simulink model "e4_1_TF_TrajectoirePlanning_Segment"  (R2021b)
settings: Solver=FixedStepAuto  StartTime=0.0  StopTime=50  FixedStep=sampleTime  RelTol=1e-3  EnableMultiTasking=on
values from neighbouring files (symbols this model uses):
  k2_d_x = 1/1    (= 1)    [e4_1_TF_TrajectoirePlanning_code.m]    (also in e4_1_Model_TrajectoirePlanning_HITL_code.m = 0.5; e4_3_Model_TrajectoirePlanning_code.m = 0.5; e4_1_Model_TrajectoirePlanning_code.m = 0.5; e4_2_TF_TrajectoirePlanning_code.m)
  k2_d_y = 1/1    (= 1)    [e4_1_TF_TrajectoirePlanning_code.m]    (also in e4_1_Model_TrajectoirePlanning_HITL_code.m = 0.377358490566; e4_3_Model_TrajectoirePlanning_code.m = 0.377358490566; e4_1_Model_TrajectoirePlanning_code.m = 0.377358490566; e4_2_TF_TrajectoirePlanning_code.m)
  k2_d_z = 10    [e4_1_TF_TrajectoirePlanning_code.m]    (also in e4_1_Model_TrajectoirePlanning_HITL_code.m; e4_3_Model_TrajectoirePlanning_code.m; e4_1_Model_TrajectoirePlanning_code.m; e4_2_TF_TrajectoirePlanning_code.m)
  k2_p_x = 1/0.8    (= 1.25)    [e4_1_TF_TrajectoirePlanning_code.m]    (also in e4_1_Model_TrajectoirePlanning_HITL_code.m = 0.645161290323; e4_3_Model_TrajectoirePlanning_code.m = 0.645161290323; e4_1_Model_TrajectoirePlanning_code.m = 0.645161290323; e4_2_TF_TrajectoirePlanning_code.m)
  k2_p_y = 1/0.8    (= 1.25)    [e4_1_TF_TrajectoirePlanning_code.m]    (also in e4_1_Model_TrajectoirePlanning_HITL_code.m = 0.4; e4_3_Model_TrajectoirePlanning_code.m = 0.4; e4_1_Model_TrajectoirePlanning_code.m = 0.4; e4_2_TF_TrajectoirePlanning_code.m)
  k2_p_yaw = 1.6    [e4_1_TF_TrajectoirePlanning_code.m]    (also in e4_1_Model_TrajectoirePlanning_HITL_code.m; e4_3_Model_TrajectoirePlanning_code.m; e4_1_Model_TrajectoirePlanning_code.m; e4_2_TF_TrajectoirePlanning_code.m)
  k2_p_z = 1    [e4_1_TF_TrajectoirePlanning_code.m]    (also in e4_1_Model_TrajectoirePlanning_HITL_code.m; e4_3_Model_TrajectoirePlanning_code.m; e4_1_Model_TrajectoirePlanning_code.m; e4_2_TF_TrajectoirePlanning_code.m)
  sampleTime = 0.01    [startSimulation.m]    (also in start.m)
  saturation_psi = 2    [startSimulation.m]    (also in start.m)
  saturation_x = 2    [startSimulation.m]    (also in start.m)
  saturation_y = 2    [startSimulation.m]    (also in start.m)
  saturation_z = 2    [startSimulation.m]    (also in start.m)
libraries: aerolibanimutils x1

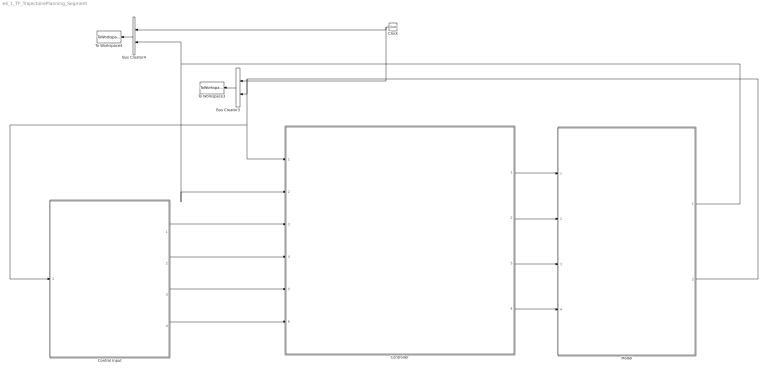
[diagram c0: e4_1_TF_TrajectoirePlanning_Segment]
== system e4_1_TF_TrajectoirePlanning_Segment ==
  Bus Creator3 : BusCreator  Inputs=2
  Bus Creator4 : BusCreator  Inputs=2
  Clock : Clock
  Control Input : Subsystem
  "Controller " : Subsystem
  Model : Subsystem
  To Workspace3 : ToWorkspace  VariableName=r1_pos_array  SampleTime=-1
  To Workspace4 : ToWorkspace  VariableName=r1_vel_array  SampleTime=-1
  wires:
  Clock/1 -> Bus Creator4/1, Bus Creator3/1
  Bus Creator3/1 -> To Workspace3/1
  Bus Creator4/1 -> To Workspace4/1
  "Controller "/1(Controller Output X) -> Model/1(Commande Input X)
  "Controller "/2(Controller Output Y) -> Model/2(Commande Input Y)
  "Controller "/3(Controller Output H) -> Model/3(Commande Input H)
  "Controller "/4(Controller Output Psi) -> Model/4(Commande Input Psi)
  Control Input/1(ux) -> "Controller "/3(Control input X)
  Control Input/2(uy) -> "Controller "/4(Control input Y)
  Control Input/3(uz) -> "Controller "/5(Control input H)
  Control Input/4(upsi) -> "Controller "/6(Control input Psi)
  Model/2(Output Position) -> "Controller "/1(Feedback Position), Control Input/1(Position Feedback), Bus Creator3/2
  Model/1(Output Velocity) -> "Controller "/2(Feedback Velocity), Bus Creator4/2

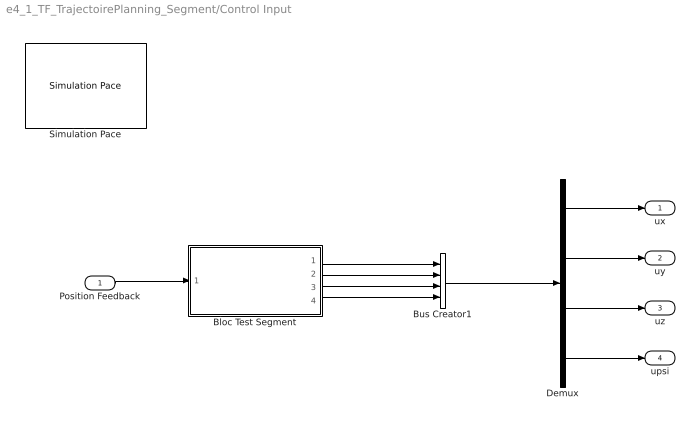
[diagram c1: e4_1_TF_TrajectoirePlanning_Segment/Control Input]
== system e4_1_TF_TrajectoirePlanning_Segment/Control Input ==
  Position Feedback : Inport
  Bloc Test Segment : Subsystem
  Bus Creator1 : BusCreator  Inputs=4
  Demux : Demux
  Simulation Pace : aerolibanimutils/Simulation Pace  SimulationPace=100  SleepMode=MATLAB Thread  OutputPaceError=off  SampleTime=-1
  ux : Outport  VectorParamsAs1DForOutWhenUnconnected=off
  uy : Outport  Port=2  VectorParamsAs1DForOutWhenUnconnected=off
  uz : Outport  Port=3  VectorParamsAs1DForOutWhenUnconnected=off
  upsi : Outport  Port=4  VectorParamsAs1DForOutWhenUnconnected=off
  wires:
  Demux/2 -> uy/1
  Demux/1 -> ux/1
  Demux/3 -> uz/1
  Demux/4 -> upsi/1
  Bloc Test Segment/4(upsi) -> Bus Creator1/4
  Bloc Test Segment/3(uz) -> Bus Creator1/3
  Bloc Test Segment/1(ux) -> Bus Creator1/1
  Bloc Test Segment/2(uy) -> Bus Creator1/2
  Bus Creator1/1 -> Demux/1
  Position Feedback/1 -> Bloc Test Segment/1(Position Feedback)

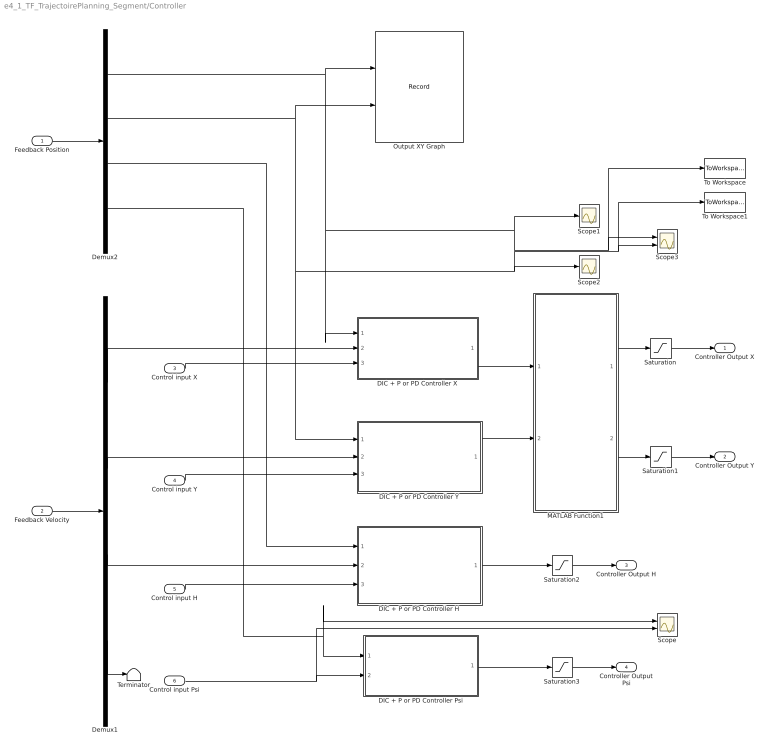
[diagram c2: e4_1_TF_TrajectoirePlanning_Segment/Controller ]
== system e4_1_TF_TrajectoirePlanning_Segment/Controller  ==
  Feedback Position : Inport
  Feedback Velocity : Inport  Port=2
  Control input X : Inport  Port=3
  Control input Y : Inport  Port=4
  Control input H : Inport  Port=5
  Control input Psi : Inport  Port=6
  DIC + P or PD Controller H : Subsystem
  DIC + P or PD Controller Psi : Subsystem
  DIC + P or PD Controller X : Subsystem
  DIC + P or PD Controller Y : Subsystem
  Demux1 : Demux
  Demux2 : Demux
  MATLAB Function1 : MATLAB Function  TreatAsAtomicUnit=on
  Output XY Graph : Record  FileSettingsInternal="{\"entries\":[{\"content\":{\"excelSettings\":{\"content\":{},\"type\":\"Streamout.ExcelSettings\"}},\"type\":\"Streamout.FileSettingStorage\",\"uuid\":\"9feb89c2-4773-4780-905a-99dce9075acd\"}],\"packageUris\":[\"http://schema.mathworks.com/mf0/streamout_blocks/R2020a\"],\"version\":\"1.0\"}"  Layout=[1 1]  SignalsInternal="{\"entries\":[{\"content\":{\"signals\":[{\"content\":{\"blockPath\":[\"e4_1_TF_TrajectoirePlanning_Segment/Controller /Output XY Graph\"],\"channel\":[],\"dimensions\":[1],\"domain\":\"e4_1_TF_TrajectoirePlanning_Segment/Controller /Output XY Graph\",\"lineColor\":\"#a2142f\",\"plots\":[1],\"port\":1,\"sid\":[\"\"],\"signalID\":2135,\"signalName\":\"Demux2:1\"},\"type\":\"RecordBlkView.Signal\",\"uuid\":\"850235fc-df35-4988-83aa-f6efe43694d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"  VisualizationBindings="{\"xyplotplugin\":{\"info\":[{\"series\":[{\"bindingParametersList\":[{\"parameter\":\"X-Axis\",\"signalID\":2135,\"signalName\":\"Demux2:1\"},{\"parameter\":\"Y-Axis\",\"signalID\":2139,\"signalName\":\"Demux2:2\"}],\"seriesID\":35699}],\"subplotID\":1}]}}"  CompatibilityTag=XY  st=-1
  Saturation : Saturate  UpperLimit=saturation_x  LowerLimit=-saturation_x
  Saturation1 : Saturate  UpperLimit=saturation_y  LowerLimit=-saturation_y
  Saturation2 : Saturate  UpperLimit=saturation_z  LowerLimit=-saturation_z
  Saturation3 : Saturate  UpperLimit=saturation_psi  LowerLimit=-saturation_psi
  Scope : Scope  NumInputPorts=2
  Scope1 : Scope
  Scope2 : Scope
  Scope3 : Scope  NumInputPorts=2
  Terminator : Terminator
  To Workspace : ToWorkspace  VariableName=x_desire  SampleTime=-1
  To Workspace1 : ToWorkspace  VariableName=y_desire  SampleTime=-1
  Controller Output X : Outport  VectorParamsAs1DForOutWhenUnconnected=off
  Controller Output Y : Outport  Port=2  VectorParamsAs1DForOutWhenUnconnected=off
  Controller Output H : Outport  Port=3  VectorParamsAs1DForOutWhenUnconnected=off
  Controller Output Psi : Outport  Port=4  VectorParamsAs1DForOutWhenUnconnected=off
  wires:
  Feedback Position/1 -> Demux2/1
  Feedback Velocity/1 -> Demux1/1
  Demux1/2 -> DIC + P or PD Controller Y/2(Feedback Velocity Y)
  Demux2/3 -> DIC + P or PD Controller H/1(Feedback Position H)
  Demux1/1 -> DIC + P or PD Controller X/2(Feedback Velocity X)
  Demux1/3 -> DIC + P or PD Controller H/2(Feedback Velocity H)
  Control input X/1 -> DIC + P or PD Controller X/3(Control Input X)
  Control input Psi/1 -> Scope/2, DIC + P or PD Controller Psi/2(Control input Psi)
  Control input H/1 -> DIC + P or PD Controller H/3(Control Input H)
  Saturation/1 -> Controller Output X/1
  Saturation1/1 -> Controller Output Y/1
  Saturation2/1 -> Controller Output H/1
  Saturation3/1 -> Controller Output Psi/1
  Control input Y/1 -> DIC + P or PD Controller Y/3(Control Input Y)
  DIC + P or PD Controller H/1(Controller Output H) -> Saturation2/1
  DIC + P or PD Controller Psi/1(Controller Output Psi) -> Saturation3/1
  Demux2/4 -> Scope/1, DIC + P or PD Controller Psi/1(Feedback Position Psi)
  Demux1/4 -> Terminator/1
  DIC + P or PD Controller X/1(Controller Output X) -> MATLAB Function1/1(eax)
  DIC + P or PD Controller Y/1(Controller Output Y) -> MATLAB Function1/2(eay)
  MATLAB Function1/2(phi) -> Saturation1/1
  MATLAB Function1/1(theta) -> Saturation/1
  Demux2/2 -> DIC + P or PD Controller Y/1(Feedback Position Y), To Workspace1/1, Scope3/2, Scope2/1, Output XY Graph/2
  Demux2/1 -> DIC + P or PD Controller X/1(Feedback Position X), To Workspace/1, Scope3/1, Scope1/1, Output XY Graph/1

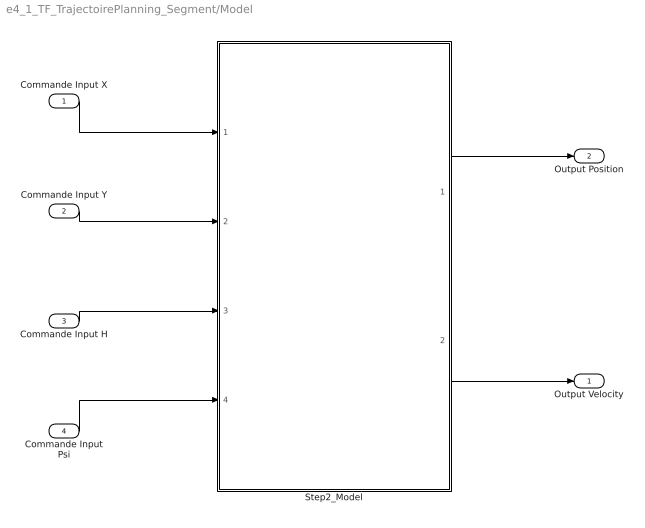
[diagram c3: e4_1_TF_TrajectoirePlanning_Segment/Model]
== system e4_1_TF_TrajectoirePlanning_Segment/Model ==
  Commande Input X : Inport
  Commande Input Y : Inport  Port=2
  Commande Input H : Inport  Port=3
  Commande Input Psi : Inport  Port=4
  Step2_Model : Subsystem
  Output Velocity : Outport  VectorParamsAs1DForOutWhenUnconnected=off
  Output Position : Outport  Port=2  VectorParamsAs1DForOutWhenUnconnected=off
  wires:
  Commande Input Y/1 -> Step2_Model/2(In2)
  Commande Input Psi/1 -> Step2_Model/4(In4)
  Commande Input H/1 -> Step2_Model/3(In3)
  Step2_Model/1(Position) -> Output Position/1
  Commande Input X/1 -> Step2_Model/1(In1)
  Step2_Model/2(Velocity) -> Output Velocity/1

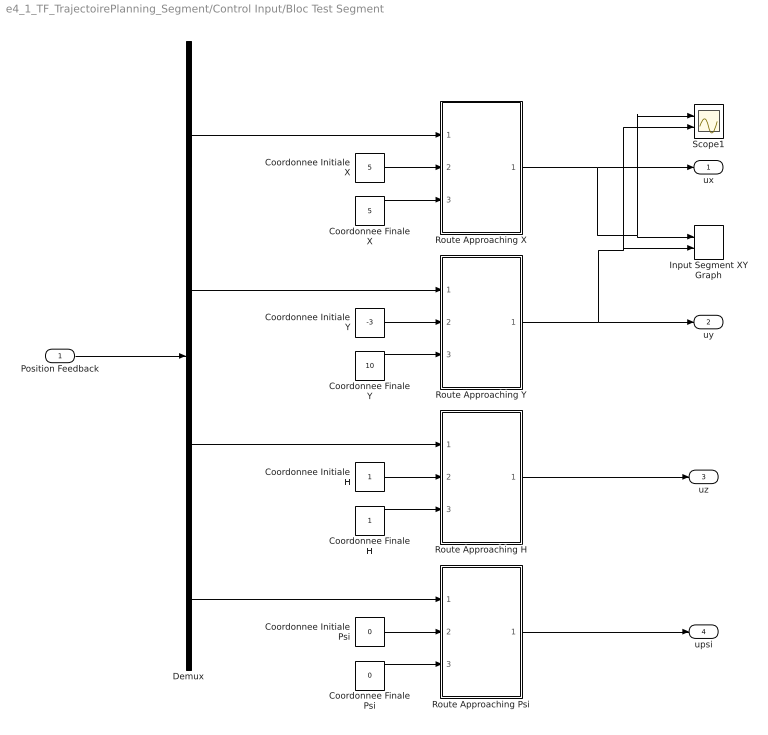
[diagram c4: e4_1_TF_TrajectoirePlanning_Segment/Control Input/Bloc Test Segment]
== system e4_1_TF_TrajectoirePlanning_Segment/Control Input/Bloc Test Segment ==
  Position Feedback : Inport
  Coordonnee Finale H : Constant
  Coordonnee Finale Psi : Constant  Value=0
  Coordonnee Finale X : Constant  Value=5
  Coordonnee Finale Y : Constant  Value=10
  Coordonnee Initiale H : Constant
  Coordonnee Initiale Psi : Constant  Value=0
  Coordonnee Initiale X : Constant  Value=5
  Coordonnee Initiale Y : Constant  Value=-3
  Demux : Demux
  Input Segment XY Graph : Record  FileSettingsInternal="{\"entries\":[{\"content\":{\"excelSettings\":{\"content\":{},\"type\":\"Streamout.ExcelSettings\"}},\"type\":\"Streamout.FileSettingStorage\",\"uuid\":\"c52b156f-2882-4037-81dc-cd67c67cff84\"}],\"packageUris\":[\"http://schema.mathworks.com/mf0/streamout_blocks/R2020a\"],\"version\":\"1.0\"}"  Layout=[1 1]  SignalsInternal="{\"entries\":[{\"content\":{\"signals\":[{\"content\":{\"blockPath\":[\"e4_1_TF_TrajectoirePlanning_Segment/Control Input/Bloc Test  Segment/Input Segment XY Graph\"],\"channel\":[],\"dimensions\":[1],\"domain\":\"e4_1_TF_TrajectoirePlanning_Segment/Control Input/Bloc Test  Segment/Input Segment XY Graph\",\"lineColor\":\"#a2142f\",\"plots\":[1],\"port\":1,\"sid\":[\"\"],\"signalID\":2127,\"signalName\":\"Route Approaching X\"},\"type\"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"  VisualizationBindings="{\"xyplotplugin\":{\"info\":[{\"series\":[{\"bindingParametersList\":[{\"parameter\":\"X-Axis\",\"signalID\":2127,\"signalName\":\"Route Approaching X\"},{\"parameter\":\"Y-Axis\",\"signalID\":2131,\"signalName\":\"Route Approaching Y\"}],\"seriesID\":20136}],\"subplotID\":1}]}}"  CompatibilityTag=XY  st=-1
  Route Approaching H : MATLAB Function  TreatAsAtomicUnit=on  SystemSampleTime=sampleTime
  Route Approaching Psi : MATLAB Function  TreatAsAtomicUnit=on  SystemSampleTime=sampleTime
  Route Approaching X : MATLAB Function  TreatAsAtomicUnit=on  SystemSampleTime=sampleTime
  Route Approaching Y : MATLAB Function  TreatAsAtomicUnit=on  SystemSampleTime=sampleTime
  Scope1 : Scope  NumInputPorts=2
  ux : Outport  VectorParamsAs1DForOutWhenUnconnected=off
  uy : Outport  Port=2  VectorParamsAs1DForOutWhenUnconnected=off
  uz : Outport  Port=3  VectorParamsAs1DForOutWhenUnconnected=off
  upsi : Outport  Port=4  VectorParamsAs1DForOutWhenUnconnected=off
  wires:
  Coordonnee Initiale X/1 -> Route Approaching X/2(P_init)
  Coordonnee Finale X/1 -> Route Approaching X/3(P_final)
  Position Feedback/1 -> Demux/1
  Demux/1 -> Route Approaching X/1(P_feedback)
  Demux/2 -> Route Approaching Y/1(P_feedback)
  Coordonnee Finale Y/1 -> Route Approaching Y/3(P_final)
  Coordonnee Initiale Y/1 -> Route Approaching Y/2(P_init)
  Route Approaching Y/1(P_d) -> Scope1/2, Input Segment XY Graph/2, uy/1
  Coordonnee Finale H/1 -> Route Approaching H/3(P_final)
  Coordonnee Initiale H/1 -> Route Approaching H/2(P_init)
  Coordonnee Finale Psi/1 -> Route Approaching Psi/3(P_final)
  Coordonnee Initiale Psi/1 -> Route Approaching Psi/2(P_init)
  Route Approaching H/1(P_d) -> uz/1
  Demux/3 -> Route Approaching H/1(P_feedback)
  Demux/4 -> Route Approaching Psi/1(P_feedback)
  Route Approaching Psi/1(P_d) -> upsi/1
  Route Approaching X/1(P_d) -> Scope1/1, Input Segment XY Graph/1, ux/1

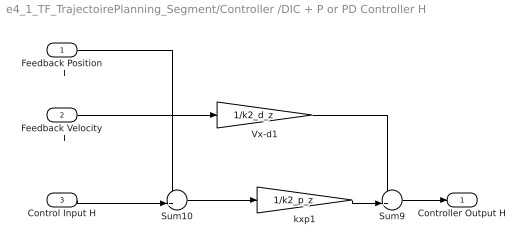
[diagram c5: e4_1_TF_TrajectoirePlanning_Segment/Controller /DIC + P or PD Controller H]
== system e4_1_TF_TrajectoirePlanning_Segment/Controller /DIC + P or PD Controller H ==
  Feedback Position H : Inport
  Feedback Velocity H : Inport  Port=2
  Control Input H : Inport  Port=3
  Sum10 : Sum  Inputs=-+|
  Sum9 : Sum  Inputs=-+|
  Vx-d1 : Gain  Gain=1/k2_d_z
  kxp1 : Gain  Gain=1/k2_p_z
  Controller Output H : Outport  VectorParamsAs1DForOutWhenUnconnected=off
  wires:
  Sum9/1 -> Controller Output H/1
  Feedback Velocity H/1 -> Vx-d1/1
  Sum10/1 -> kxp1/1
  kxp1/1 -> Sum9/2
  Vx-d1/1 -> Sum9/1
  Control Input H/1 -> Sum10/2
  Feedback Position H/1 -> Sum10/1

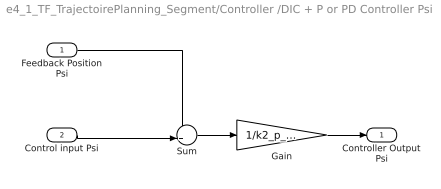
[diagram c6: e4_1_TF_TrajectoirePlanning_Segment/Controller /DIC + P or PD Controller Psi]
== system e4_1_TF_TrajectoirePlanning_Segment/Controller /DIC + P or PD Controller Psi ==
  Feedback Position Psi : Inport
  Control input Psi : Inport  Port=2
  Gain : Gain  Gain=1/k2_p_yaw
  Sum : Sum  Inputs=-+|
  Controller Output Psi : Outport  VectorParamsAs1DForOutWhenUnconnected=off
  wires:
  Gain/1 -> Controller Output Psi/1
  Sum/1 -> Gain/1
  Control input Psi/1 -> Sum/2
  Feedback Position Psi/1 -> Sum/1

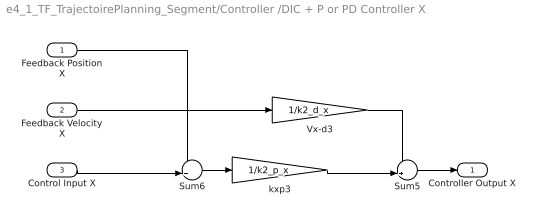
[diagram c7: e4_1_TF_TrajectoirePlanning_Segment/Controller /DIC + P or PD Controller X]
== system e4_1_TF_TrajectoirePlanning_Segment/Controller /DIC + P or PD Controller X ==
  Feedback Position X : Inport
  Feedback Velocity X : Inport  Port=2
  Control Input X : Inport  Port=3
  Sum5 : Sum  Inputs=-+|
  Sum6 : Sum  Inputs=-+|
  Vx-d3 : Gain  Gain=1/k2_d_x
  kxp3 : Gain  Gain=1/k2_p_x
  Controller Output X : Outport  VectorParamsAs1DForOutWhenUnconnected=off
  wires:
  Vx-d3/1 -> Sum5/1
  kxp3/1 -> Sum5/2
  Sum5/1 -> Controller Output X/1
  Sum6/1 -> kxp3/1
  Control Input X/1 -> Sum6/2
  Feedback Velocity X/1 -> Vx-d3/1
  Feedback Position X/1 -> Sum6/1

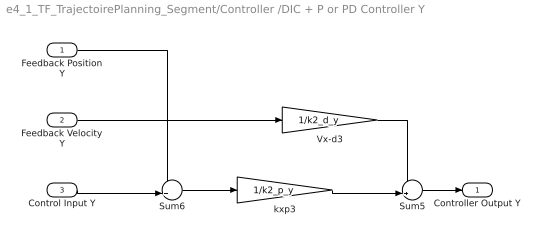
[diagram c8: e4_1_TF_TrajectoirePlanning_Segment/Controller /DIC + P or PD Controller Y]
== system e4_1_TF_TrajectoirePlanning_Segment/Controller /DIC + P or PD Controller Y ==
  Feedback Position Y : Inport
  Feedback Velocity Y : Inport  Port=2
  Control Input Y : Inport  Port=3
  Sum5 : Sum  Inputs=-+|
  Sum6 : Sum  Inputs=-+|
  Vx-d3 : Gain  Gain=1/k2_d_y
  kxp3 : Gain  Gain=1/k2_p_y
  Controller Output Y : Outport  VectorParamsAs1DForOutWhenUnconnected=off
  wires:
  Feedback Velocity Y/1 -> Vx-d3/1
  Feedback Position Y/1 -> Sum6/1
  Sum6/1 -> kxp3/1
  kxp3/1 -> Sum5/2
  Vx-d3/1 -> Sum5/1
  Sum5/1 -> Controller Output Y/1
  Control Input Y/1 -> Sum6/2

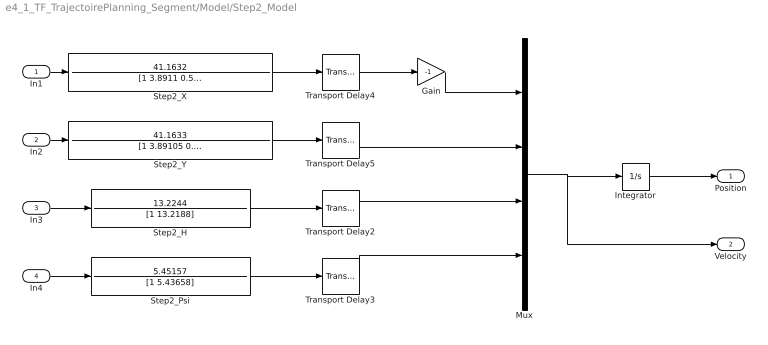
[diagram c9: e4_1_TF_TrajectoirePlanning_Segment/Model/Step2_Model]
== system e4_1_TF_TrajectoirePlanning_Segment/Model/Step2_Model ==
  In1 : Inport
  In2 : Inport  Port=2
  In3 : Inport  Port=3
  In4 : Inport  Port=4
  Gain : Gain  Gain=-1
  Integrator : Integrator
  Mux : Mux
  Step2_H : TransferFcn  Numerator=13.2244  Denominator=[1 13.2188]
  Step2_Psi : TransferFcn  Numerator=5.45157  Denominator=[1 5.43658]
  Step2_X : TransferFcn  Numerator=41.1632  Denominator=[1 3.8911 0.529635]
  Step2_Y : TransferFcn  Numerator=41.1633  Denominator=[1 3.89105 0.529839]
  Transport Delay2 : TransportDelay  DelayTime=0.0344
  Transport Delay3 : TransportDelay  DelayTime=0.0313
  Transport Delay4 : TransportDelay  DelayTime=0.0289
  Transport Delay5 : TransportDelay  DelayTime=0.0289
  Position : Outport  VectorParamsAs1DForOutWhenUnconnected=off
  Velocity : Outport  Port=2  VectorParamsAs1DForOutWhenUnconnected=off
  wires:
  Transport Delay2/1 -> Mux/3
  In2/1 -> Step2_Y/1
  In4/1 -> Step2_Psi/1
  Transport Delay3/1 -> Mux/4
  In1/1 -> Step2_X/1
  In3/1 -> Step2_H/1
  Step2_H/1 -> Transport Delay2/1
  Step2_Y/1 -> Transport Delay5/1
  Step2_X/1 -> Transport Delay4/1
  Step2_Psi/1 -> Transport Delay3/1
  Transport Delay4/1 -> Gain/1
  Transport Delay5/1 -> Mux/2
  Integrator/1 -> Position/1
  Mux/1 -> Velocity/1, Integrator/1
  Gain/1 -> Mux/1

== matlab function e4_1_TF_TrajectoirePlanning_Segment/Control Input/Bloc Test 
Segment/Route Approaching Y ==
function P_d = fcn(P_feedback, P_init, P_final)

% determine the constants
a0  =1;

% the parameters of PD controller: 1/k2
% according to P287 of 《多旋翼飞行器设计与控制》,
% these two parameters should be equal? Is that true?

% global k2_p_y;
% global k2_d_y;
% k2_p_y=0.1;
% k2_d_y=0.1;

% the parameter of 'approaching'
k0_y=0.3;
k1_y=1;

persistent P_static;
if isempty(P_static)
    P_static=0; % the initilized value of position for giving a initial UAV position
else
    P_static = P_feedback;
end

% P_static = P_feedback;

% the iterative process
P_perp = P_final+(P_init-P_final)*((P_static-P_final)'*(P_init-P_final))/(norm(P_final-P_init + 0.000001))^2;
% this extra '+ 0.000001' is for avoiding that 
% the zero denominator turns to zero.

temp  = k1_y*satgd(((k0_y/k1_y)*(P_final - P_static)+(P_perp-P_static)),a0);
% temp  = k0_y*satgd(((P_final - P_static)+(k1_y/k0_y)*(P_perp-P_static)),a0);

P_d = P_static + temp;

== matlab function e4_1_TF_TrajectoirePlanning_Segment/Control Input/Bloc Test 
Segment/Route Approaching X ==
function P_d = fcn(P_feedback, P_init, P_final)

% determine the constants
a0  =1;

% the parameters of PD controller: 1/k2
% according to P287 of 《多旋翼飞行器设计与控制》,
% these two parameters should be equal? Is that true?

% global k2_p_x;
% global k2_d_x;
% k2_p_x=0.1;
% k2_d_x=0.1;

% the parameter of 'approaching'
k0_x=0.2;
k1_x=1;

persistent P_static;
if isempty(P_static)
    P_static=0; % the initilized value of position for giving a initial UAV position
else
    P_static = P_feedback;
end



% the iterative process
P_perp = P_final+(P_init-P_final)*((P_static-P_final)'*(P_init-P_final))/(norm(P_final-P_init + 0.000001))^2;
% this extra '+ 0.000001' is for avoiding that 
% the zero denominator turns to zero.

temp  = k1_x*satgd(((k0_x/k1_x)*(P_final - P_static)+(P_perp-P_static)),a0);
% temp  = k0_x*satgd(((P_final - P_static)+(k1_x/k0_x)*(P_perp-P_static)),a0);

P_d = P_static + temp;

== matlab function e4_1_TF_TrajectoirePlanning_Segment/Control Input/Bloc Test 
Segment/Route Approaching H ==
function P_d = fcn(P_feedback, P_init, P_final)

% determine the constants
a0  = 10;

% the parameters of PD controller: 1/k2
% according to P287 of 《多旋翼飞行器设计与控制》,
% these two parameters should be equal? Is that true?

% global k2_p_z;
% global k2_d_z;
% k2_p_z=0.1;
% k2_d_z=0.1;

% the parameter of 'approaching'
k0_z=0.1;
k1_z=1;

persistent P_static;
if isempty(P_static)
    P_static=0; % the initilized value of position for giving a initial UAV position
end

P_static = P_feedback;

% the iterative process
P_perp = P_final+(P_init-P_final)*((P_static-P_final)'*(P_init-P_final))/(norm(P_final-P_init + 0.000001))^2;
% this extra '+ 0.000001' is for avoiding that 
% the zero denominator turns to zero.
temp  = satgd(k0_z*(P_final - P_static)+k1_z*(P_perp-P_static),a0);
P_d = P_static + temp;

== matlab function e4_1_TF_TrajectoirePlanning_Segment/Control Input/Bloc Test 
Segment/Route Approaching Psi ==
function P_d = fcn(P_feedback, P_init, P_final)

% determine the constants
a0  = 10;

% the parameters of PD controller: 1/k2
% according to P287 of 《多旋翼飞行器设计与控制》,
% these two parameters should be equal? Is that true?

% global k2_p_yaw;
% global k2_d_yaw;
% k2_p_yaw=0.1;
% k2_d_yaw=0.1;

% the parameter of 'approaching'
k0_yaw=0.1;
k1_yaw=1;

persistent P_static;
if isempty(P_static)
    P_static=0; % the initilized value of position for giving a initial UAV position
end

P_static = P_feedback;

% the iterative process
P_perp = P_final+(P_init-P_final)*((P_static-P_final)'*(P_init-P_final))/(norm(P_final-P_init + 0.000001))^2;
% this extra '+ 0.000001' is for avoiding that 
% the zero denominator turns to zero.
temp  = satgd(k0_yaw*(P_final - P_static)+k1_yaw*(P_perp-P_static),a0);
P_d = P_static + temp;

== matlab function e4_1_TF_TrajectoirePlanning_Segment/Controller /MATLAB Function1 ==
function [theta,phi] = fcn(eax,eay)
g=9.8;

theta =-eax/g;% vx
phi =eay/g;% vy
